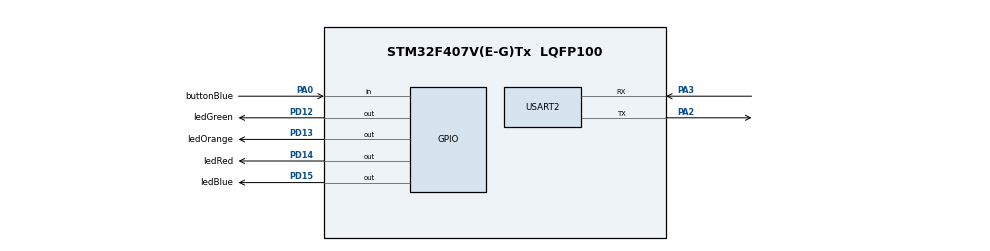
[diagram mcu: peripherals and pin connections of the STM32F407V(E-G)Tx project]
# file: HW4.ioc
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Mcu.Family=STM32F4
Mcu.Name=STM32F407V(E-G)Tx
Mcu.Package=LQFP100
NVIC.PriorityGroup=NVIC_PRIORITYGROUP_4
NVIC.TIM7_IRQn=true\:15\:0\:false\:false\:true\:false\:true\:true
NVIC.TimeBase=TIM7_IRQn
NVIC.TimeBaseIP=TIM7
PA0-WKUP.GPIO_Label=buttonBlue
PA0-WKUP.Signal=GPIO_Input
PA13.Mode=Serial_Wire
PA13.Signal=SYS_JTMS-SWDIO
PA14.Mode=Serial_Wire
PA14.Signal=SYS_JTCK-SWCLK
PA2.Mode=Asynchronous
PA2.Signal=USART2_TX
PA3.Mode=Asynchronous
PA3.Signal=USART2_RX
PD12.GPIO_Label=ledGreen
PD12.Signal=GPIO_Output
PD13.GPIO_Label=ledOrange
PD13.Signal=GPIO_Output
PD14.GPIO_Label=ledRed
PD14.Signal=GPIO_Output
PD15.GPIO_Label=ledBlue
PD15.Signal=GPIO_Output
ProjectManager.HeapSize=0x200
ProjectManager.StackSize=0x400
ProjectManager.TargetToolchain=STM32CubeIDE
RCC.AHBFreq_Value=16000000
RCC.APB1Freq_Value=16000000
RCC.APB2Freq_Value=16000000
RCC.CortexFreq_Value=16000000
RCC.HSE_VALUE=25000000
RCC.HSI_VALUE=16000000
RCC.LSE_VALUE=32768
RCC.SYSCLKFreq_VALUE=16000000
RCC.VCOOutputFreq_Value=192000000
USART2.VirtualMode=VM_ASYNC
VP_SYS_VS_tim7.Mode=TIM7
board=custom

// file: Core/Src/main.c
/* USER CODE BEGIN Header */
/**
  ******************************************************************************
  * @file           : main.c
  * @brief          : Main program body
  ******************************************************************************
  * @attention
  *
  * Copyright (c) 2022 STMicroelectronics.
  * All rights reserved.
  *
  * This software is licensed under terms that can be found in the LICENSE file
  * in the root directory of this software component.
  * If no LICENSE file comes with this software, it is provided AS-IS.
  *
  ******************************************************************************
  */
/* USER CODE END Header */
#include "main.h"

/* USER CODE BEGIN Includes */
#include "FreeRTOS.h"
#include "task.h"
/* USER CODE END Includes */

UART_HandleTypeDef huart2;

void SystemClock_Config(void);
static void MX_GPIO_Init(void);
static void MX_USART2_UART_Init(void);

/* USER CODE BEGIN 0 */
void red_LED_task(void *pvParameters)
{
	while (1) {
		HAL_GPIO_TogglePin(GPIOD, GPIO_PIN_14);
		vTaskDelay(500);
	}
}

void green_LED_task(void *pvParameters)
{
	while (1) {
		HAL_GPIO_TogglePin(GPIOD, GPIO_PIN_12);
		vTaskDelay(1000);
	}
}

void task1(void *pvParameters)
{
    while (1) {
        vTaskDelete(NULL);
    }
}

void task2(void *pvParameters)
{
    while (1) {
        vTaskDelete(NULL);
    }
}

void task3(void *pvParameters)
{
    while (1) {
        vTaskDelete(NULL);
    }
}

void print_task(void *pvParameters)
{
    while (1) {
		vPrintFreeList();
		vTaskDelay(3000);
	}
}
/* USER CODE END 0 */

int main(void)
{

  /* MCU Configuration--------------------------------------------------------*/

  /* Reset of all peripherals, Initializes the Flash interface and the Systick. */
  HAL_Init();

  /* Configure the system clock */
  SystemClock_Config();

  /* Initialize all configured peripherals */
  MX_GPIO_Init();
  MX_USART2_UART_Init();
  /* USER CODE BEGIN 2 */
  xTaskCreate(red_LED_task, "RED_LED", 100, NULL, 0, NULL);
  xTaskCreate(task1, "TASK1", 50, NULL, 0, NULL);
  xTaskCreate(task2, "TASK2", 30, NULL, 0, NULL);
  xTaskCreate(green_LED_task, "GREEN_LED", 130, NULL, 0, NULL);
  xTaskCreate(task3, "TASK3", 40, NULL, 0, NULL);
  xTaskCreate(print_task, "PRINT", 130, NULL, 0, NULL);
  vTaskStartScheduler();
  /* USER CODE END 2 */

  /* Infinite loop */
  while (1)
  {

  }
}

void SystemClock_Config(void)
{
  RCC_OscInitTypeDef RCC_OscInitStruct = {0};
  RCC_ClkInitTypeDef RCC_ClkInitStruct = {0};

  /** Configure the main internal regulator output voltage
  */
  __HAL_RCC_PWR_CLK_ENABLE();
  __HAL_PWR_VOLTAGESCALING_CONFIG(PWR_REGULATOR_VOLTAGE_SCALE1);
  /** Initializes the RCC Oscillators according to the specified parameters
  * in the RCC_OscInitTypeDef structure.
  */
  RCC_OscInitStruct.OscillatorType = RCC_OSCILLATORTYPE_HSI;
  RCC_OscInitStruct.HSIState = RCC_HSI_ON;
  RCC_OscInitStruct.HSICalibrationValue = RCC_HSICALIBRATION_DEFAULT;
  RCC_OscInitStruct.PLL.PLLState = RCC_PLL_ON;
  RCC_OscInitStruct.PLL.PLLSource = RCC_PLLSOURCE_HSI;
  RCC_OscInitStruct.PLL.PLLM = 8;
  RCC_OscInitStruct.PLL.PLLN = 50;
  RCC_OscInitStruct.PLL.PLLP = RCC_PLLP_DIV4;
  RCC_OscInitStruct.PLL.PLLQ = 7;
  if (HAL_RCC_OscConfig(&RCC_OscInitStruct) != HAL_OK)
  {
    Error_Handler();
  }
  /** Initializes the CPU, AHB and APB buses clocks
  */
  RCC_ClkInitStruct.ClockType = RCC_CLOCKTYPE_HCLK|RCC_CLOCKTYPE_SYSCLK
                              |RCC_CLOCKTYPE_PCLK1|RCC_CLOCKTYPE_PCLK2;
  RCC_ClkInitStruct.SYSCLKSource = RCC_SYSCLKSOURCE_PLLCLK;
  RCC_ClkInitStruct.AHBCLKDivider = RCC_SYSCLK_DIV1;
  RCC_ClkInitStruct.APB1CLKDivider = RCC_HCLK_DIV4;
  RCC_ClkInitStruct.APB2CLKDivider = RCC_HCLK_DIV2;

  if (HAL_RCC_ClockConfig(&RCC_ClkInitStruct, FLASH_LATENCY_0) != HAL_OK)
  {
    Error_Handler();
  }
}

static void MX_USART2_UART_Init(void)
{

  huart2.Instance = USART2;
  huart2.Init.BaudRate = 115200;
  huart2.Init.WordLength = UART_WORDLENGTH_8B;
  huart2.Init.StopBits = UART_STOPBITS_1;
  huart2.Init.Parity = UART_PARITY_NONE;
  huart2.Init.Mode = UART_MODE_TX_RX;
  huart2.Init.HwFlowCtl = UART_HWCONTROL_NONE;
  huart2.Init.OverSampling = UART_OVERSAMPLING_16;
  if (HAL_UART_Init(&huart2) != HAL_OK)
  {
    Error_Handler();
  }

}

static void MX_GPIO_Init(void)
{
  GPIO_InitTypeDef GPIO_InitStruct = {0};

  /* GPIO Ports Clock Enable */
  __HAL_RCC_GPIOE_CLK_ENABLE();
  __HAL_RCC_GPIOC_CLK_ENABLE();
  __HAL_RCC_GPIOH_CLK_ENABLE();
  __HAL_RCC_GPIOA_CLK_ENABLE();
  __HAL_RCC_GPIOB_CLK_ENABLE();
  __HAL_RCC_GPIOD_CLK_ENABLE();

  /*Configure GPIO pin Output Level */
  //HAL_GPIO_WritePin(CS_I2C_SPI_GPIO_Port, CS_I2C_SPI_Pin, GPIO_PIN_RESET);

  /*Configure GPIO pin Output Level */
  //HAL_GPIO_WritePin(OTG_FS_PowerSwitchOn_GPIO_Port, OTG_FS_PowerSwitchOn_Pin, GPIO_PIN_SET);

  /*Configure GPIO pin Output Level */
  //HAL_GPIO_WritePin(GPIOD, LD4_Pin|LD3_Pin|LD5_Pin|LD6_Pin
  //                        |Audio_RST_Pin, GPIO_PIN_RESET);

  /*Configure GPIO pin : CS_I2C_SPI_Pin */
  //GPIO_InitStruct.Pin = CS_I2C_SPI_Pin;
  GPIO_InitStruct.Mode = GPIO_MODE_OUTPUT_PP;
  GPIO_InitStruct.Pull = GPIO_NOPULL;
  GPIO_InitStruct.Speed = GPIO_SPEED_FREQ_LOW;
  //HAL_GPIO_Init(CS_I2C_SPI_GPIO_Port, &GPIO_InitStruct);

  /*Configure GPIO pin : OTG_FS_PowerSwitchOn_Pin */
  //GPIO_InitStruct.Pin = OTG_FS_PowerSwitchOn_Pin;
  GPIO_InitStruct.Mode = GPIO_MODE_OUTPUT_PP;
  GPIO_InitStruct.Pull = GPIO_NOPULL;
  GPIO_InitStruct.Speed = GPIO_SPEED_FREQ_LOW;
  //HAL_GPIO_Init(OTG_FS_PowerSwitchOn_GPIO_Port, &GPIO_InitStruct);

  /*Configure GPIO pin : PDM_OUT_Pin */
  //GPIO_InitStruct.Pin = PDM_OUT_Pin;
  GPIO_InitStruct.Mode = GPIO_MODE_AF_PP;
  GPIO_InitStruct.Pull = GPIO_NOPULL;
  GPIO_InitStruct.Speed = GPIO_SPEED_FREQ_LOW;
  GPIO_InitStruct.Alternate = GPIO_AF5_SPI2;
  //HAL_GPIO_Init(PDM_OUT_GPIO_Port, &GPIO_InitStruct);

  /*Configure GPIO pin : B1_Pin */
  //GPIO_InitStruct.Pin = B1_Pin;
  GPIO_InitStruct.Mode = GPIO_MODE_IT_RISING;
  GPIO_InitStruct.Pull = GPIO_NOPULL;
  //HAL_GPIO_Init(B1_GPIO_Port, &GPIO_InitStruct);

  /*Configure GPIO pin : I2S3_WS_Pin */
  //GPIO_InitStruct.Pin = I2S3_WS_Pin;
  GPIO_InitStruct.Mode = GPIO_MODE_AF_PP;
  GPIO_InitStruct.Pull = GPIO_NOPULL;
  GPIO_InitStruct.Speed = GPIO_SPEED_FREQ_LOW;
  GPIO_InitStruct.Alternate = GPIO_AF6_SPI3;
  //HAL_GPIO_Init(I2S3_WS_GPIO_Port, &GPIO_InitStruct);

  /*Configure GPIO pins : SPI1_SCK_Pin SPI1_MISO_Pin SPI1_MOSI_Pin */
  //GPIO_InitStruct.Pin = SPI1_SCK_Pin|SPI1_MISO_Pin|SPI1_MOSI_Pin;
  GPIO_InitStruct.Mode = GPIO_MODE_AF_PP;
  GPIO_InitStruct.Pull = GPIO_NOPULL;
  GPIO_InitStruct.Speed = GPIO_SPEED_FREQ_LOW;
  GPIO_InitStruct.Alternate = GPIO_AF5_SPI1;
  HAL_GPIO_Init(GPIOA, &GPIO_InitStruct);

  /*Configure GPIO pin : BOOT1_Pin */
  //GPIO_InitStruct.Pin = BOOT1_Pin;
  GPIO_InitStruct.Mode = GPIO_MODE_INPUT;
  GPIO_InitStruct.Pull = GPIO_NOPULL;
  //HAL_GPIO_Init(BOOT1_GPIO_Port, &GPIO_InitStruct);

  /*Configure GPIO pin : CLK_IN_Pin */
  //GPIO_InitStruct.Pin = CLK_IN_Pin;
  GPIO_InitStruct.Mode = GPIO_MODE_AF_PP;
  GPIO_InitStruct.Pull = GPIO_NOPULL;
  GPIO_InitStruct.Speed = GPIO_SPEED_FREQ_LOW;
  GPIO_InitStruct.Alternate = GPIO_AF5_SPI2;
  //HAL_GPIO_Init(CLK_IN_GPIO_Port, &GPIO_InitStruct);

  /*Configure GPIO pins : LD4_Pin LD3_Pin LD5_Pin LD6_Pin
                           Audio_RST_Pin */
  //GPIO_InitStruct.Pin = LD4_Pin|LD3_Pin|LD5_Pin|LD6_Pin
  //                        |Audio_RST_Pin;
  GPIO_InitStruct.Mode = GPIO_MODE_OUTPUT_PP;
  GPIO_InitStruct.Pull = GPIO_NOPULL;
  GPIO_InitStruct.Speed = GPIO_SPEED_FREQ_LOW;
  HAL_GPIO_Init(GPIOD, &GPIO_InitStruct);

  /*Configure GPIO pins : I2S3_MCK_Pin I2S3_SCK_Pin I2S3_SD_Pin */
  //GPIO_InitStruct.Pin = I2S3_MCK_Pin|I2S3_SCK_Pin|I2S3_SD_Pin;
  GPIO_InitStruct.Mode = GPIO_MODE_AF_PP;
  GPIO_InitStruct.Pull = GPIO_NOPULL;
  GPIO_InitStruct.Speed = GPIO_SPEED_FREQ_LOW;
  GPIO_InitStruct.Alternate = GPIO_AF6_SPI3;
  HAL_GPIO_Init(GPIOC, &GPIO_InitStruct);

  /*Configure GPIO pin : VBUS_FS_Pin */
  //GPIO_InitStruct.Pin = VBUS_FS_Pin;
  GPIO_InitStruct.Mode = GPIO_MODE_INPUT;
  GPIO_InitStruct.Pull = GPIO_NOPULL;
  //HAL_GPIO_Init(VBUS_FS_GPIO_Port, &GPIO_InitStruct);

  /*Configure GPIO pins : OTG_FS_ID_Pin OTG_FS_DM_Pin OTG_FS_DP_Pin */
  //GPIO_InitStruct.Pin = OTG_FS_ID_Pin|OTG_FS_DM_Pin|OTG_FS_DP_Pin;
  GPIO_InitStruct.Mode = GPIO_MODE_AF_PP;
  GPIO_InitStruct.Pull = GPIO_NOPULL;
  GPIO_InitStruct.Speed = GPIO_SPEED_FREQ_LOW;
  GPIO_InitStruct.Alternate = GPIO_AF10_OTG_FS;
  HAL_GPIO_Init(GPIOA, &GPIO_InitStruct);

  /*Configure GPIO pin : OTG_FS_OverCurrent_Pin */
  //GPIO_InitStruct.Pin = OTG_FS_OverCurrent_Pin;
  GPIO_InitStruct.Mode = GPIO_MODE_INPUT;
  GPIO_InitStruct.Pull = GPIO_NOPULL;
  //HAL_GPIO_Init(OTG_FS_OverCurrent_GPIO_Port, &GPIO_InitStruct);

  /*Configure GPIO pins : Audio_SCL_Pin Audio_SDA_Pin */
  //GPIO_InitStruct.Pin = Audio_SCL_Pin|Audio_SDA_Pin;
  GPIO_InitStruct.Mode = GPIO_MODE_AF_OD;
  GPIO_InitStruct.Pull = GPIO_NOPULL;
  GPIO_InitStruct.Speed = GPIO_SPEED_FREQ_LOW;
  GPIO_InitStruct.Alternate = GPIO_AF4_I2C1;
  HAL_GPIO_Init(GPIOB, &GPIO_InitStruct);

  /*Configure GPIO pin : MEMS_INT2_Pin */
  //GPIO_InitStruct.Pin = MEMS_INT2_Pin;
  GPIO_InitStruct.Mode = GPIO_MODE_EVT_RISING;
  GPIO_InitStruct.Pull = GPIO_NOPULL;
  //HAL_GPIO_Init(MEMS_INT2_GPIO_Port, &GPIO_InitStruct);

}

void HAL_TIM_PeriodElapsedCallback(TIM_HandleTypeDef *htim)
{
  if (htim->Instance == TIM7) {
    HAL_IncTick();
  }
}

void Error_Handler(void)
{
  __disable_irq();
  while (1)
  {
  }
}
